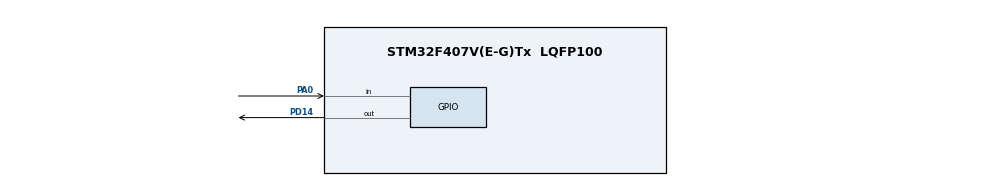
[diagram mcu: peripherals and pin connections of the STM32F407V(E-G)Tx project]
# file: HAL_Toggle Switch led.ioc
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Mcu.Family=STM32F4
Mcu.Name=STM32F407V(E-G)Tx
Mcu.Package=LQFP100
NVIC.PriorityGroup=NVIC_PRIORITYGROUP_0
PA0-WKUP.Signal=GPIO_Input
PD14.Signal=GPIO_Output
ProjectManager.HeapSize=0x200
ProjectManager.StackSize=0x400
ProjectManager.TargetToolchain=STM32CubeIDE
RCC.48MHZClocksFreq_Value=14285714.285714285
RCC.AHBFreq_Value=25000000
RCC.APB1CLKDivider=RCC_HCLK_DIV4
RCC.APB1Freq_Value=6250000
RCC.APB1TimFreq_Value=12500000
RCC.APB2CLKDivider=RCC_HCLK_DIV2
RCC.APB2Freq_Value=12500000
RCC.APB2TimFreq_Value=25000000
RCC.CortexFreq_Value=25000000
RCC.HCLKFreq_Value=25000000
RCC.HSE_VALUE=8000000
RCC.HSI_VALUE=16000000
RCC.LSE_VALUE=32768
RCC.PLLM=8
RCC.PLLN=50
RCC.PLLP=RCC_PLLP_DIV4
RCC.PLLQ=7
RCC.SYSCLKFreq_VALUE=25000000
RCC.SYSCLKSource=RCC_SYSCLKSOURCE_PLLCLK
RCC.VCOOutputFreq_Value=100000000
board=STM32F407G-DISC1

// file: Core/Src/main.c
/* USER CODE BEGIN Header */
/**
  ******************************************************************************
  * @file           : main.c
  * @brief          : Main program body
  ******************************************************************************
  * @attention
  *
  * Copyright (c) 2025 STMicroelectronics.
  * All rights reserved.
  *
  * This software is licensed under terms that can be found in the LICENSE file
  * in the root directory of this software component.
  * If no LICENSE file comes with this software, it is provided AS-IS.
  *
  ******************************************************************************
  */
/* USER CODE END Header */
#include "main.h"

void SystemClock_Config(void);
static void MX_GPIO_Init(void);

int main(void)
{

  /* MCU Configuration--------------------------------------------------------*/

  /* Reset of all peripherals, Initializes the Flash interface and the Systick. */
  HAL_Init();

  /* Configure the system clock */
  SystemClock_Config();

  /* Initialize all configured peripherals */
  MX_GPIO_Init();

  /* Infinite loop */
  while (1)
  {

    /* USER CODE BEGIN 3 */
	  if (HAL_GPIO_ReadPin(GPIOA, GPIO_PIN_0) == GPIO_PIN_SET)
	  	  {
	  		HAL_GPIO_TogglePin(GPIOD, GPIO_PIN_14);
	  		HAL_Delay(1000);
	  	}
  }
  /* USER CODE END 3 */
}

void SystemClock_Config(void)
{
  RCC_OscInitTypeDef RCC_OscInitStruct = {0};
  RCC_ClkInitTypeDef RCC_ClkInitStruct = {0};

  /** Configure the main internal regulator output voltage
  */
  __HAL_RCC_PWR_CLK_ENABLE();
  __HAL_PWR_VOLTAGESCALING_CONFIG(PWR_REGULATOR_VOLTAGE_SCALE1);

  /** Initializes the RCC Oscillators according to the specified parameters
  * in the RCC_OscInitTypeDef structure.
  */
  RCC_OscInitStruct.OscillatorType = RCC_OSCILLATORTYPE_HSE;
  RCC_OscInitStruct.HSEState = RCC_HSE_ON;
  RCC_OscInitStruct.PLL.PLLState = RCC_PLL_ON;
  RCC_OscInitStruct.PLL.PLLSource = RCC_PLLSOURCE_HSE;
  RCC_OscInitStruct.PLL.PLLM = 8;
  RCC_OscInitStruct.PLL.PLLN = 336;
  RCC_OscInitStruct.PLL.PLLP = RCC_PLLP_DIV2;
  RCC_OscInitStruct.PLL.PLLQ = 7;
  if (HAL_RCC_OscConfig(&RCC_OscInitStruct) != HAL_OK)
  {
    Error_Handler();
  }

  /** Initializes the CPU, AHB and APB buses clocks
  */
  RCC_ClkInitStruct.ClockType = RCC_CLOCKTYPE_HCLK|RCC_CLOCKTYPE_SYSCLK
                              |RCC_CLOCKTYPE_PCLK1|RCC_CLOCKTYPE_PCLK2;
  RCC_ClkInitStruct.SYSCLKSource = RCC_SYSCLKSOURCE_PLLCLK;
  RCC_ClkInitStruct.AHBCLKDivider = RCC_SYSCLK_DIV1;
  RCC_ClkInitStruct.APB1CLKDivider = RCC_HCLK_DIV4;
  RCC_ClkInitStruct.APB2CLKDivider = RCC_HCLK_DIV2;

  if (HAL_RCC_ClockConfig(&RCC_ClkInitStruct, FLASH_LATENCY_5) != HAL_OK)
  {
    Error_Handler();
  }
}

static void MX_GPIO_Init(void)
{
  GPIO_InitTypeDef GPIO_InitStruct = {0};

  /* GPIO Ports Clock Enable */
  __HAL_RCC_GPIOA_CLK_ENABLE();
  __HAL_RCC_GPIOD_CLK_ENABLE();

  /*Configure GPIO pin Output Level */
  HAL_GPIO_WritePin(GPIOD, GPIO_PIN_14, GPIO_PIN_RESET);

  /*Configure GPIO pin : PA0 */
  GPIO_InitStruct.Pin = GPIO_PIN_0;
  GPIO_InitStruct.Mode = GPIO_MODE_INPUT;
  GPIO_InitStruct.Pull = GPIO_PULLDOWN;
  HAL_GPIO_Init(GPIOA, &GPIO_InitStruct);

  /*Configure GPIO pin : PD14 */
  GPIO_InitStruct.Pin = GPIO_PIN_14;
  GPIO_InitStruct.Mode = GPIO_MODE_OUTPUT_PP;
  GPIO_InitStruct.Pull = GPIO_PULLDOWN;
  GPIO_InitStruct.Speed = GPIO_SPEED_FREQ_LOW;
  HAL_GPIO_Init(GPIOD, &GPIO_InitStruct);

}

void Error_Handler(void)
{
  __disable_irq();
  while (1)
  {
  }
}
